VERSION 5.7 ;
  NOWIREEXTENSIONATPIN ON ;
  DIVIDERCHAR "/" ;
  BUSBITCHARS "[]" ;
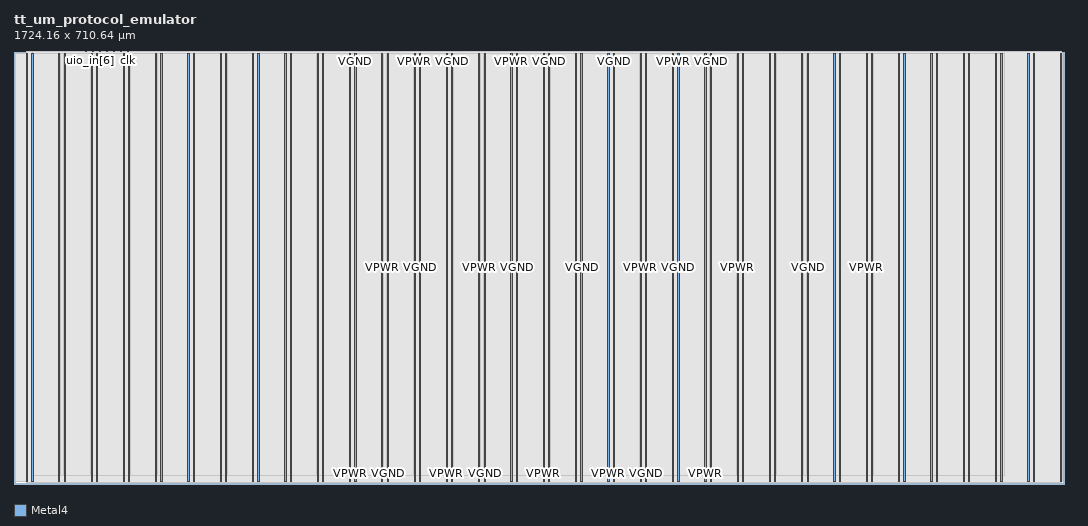
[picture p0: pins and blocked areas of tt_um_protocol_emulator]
MACRO tt_um_protocol_emulator
  CLASS BLOCK ;
  FOREIGN tt_um_protocol_emulator ;
  ORIGIN 0.000 0.000 ;
  SIZE 1724.160 BY 710.640 ;
  PIN VGND
    DIRECTION INOUT ;
    USE GROUND ;
    PORT
      LAYER Metal4 ;
        RECT 1143.055 3.560 1145.155 707.080 ;
    END
  END VGND
  PIN VGND
    DIRECTION INOUT ;
    USE GROUND ;
    PORT
      LAYER Metal4 ;
        RECT 1090.015 3.560 1092.115 707.080 ;
    END
  END VGND
  PIN VGND
    DIRECTION INOUT ;
    USE GROUND ;
    PORT
      LAYER Metal4 ;
        RECT 1036.975 3.560 1039.075 707.080 ;
    END
  END VGND
  PIN VGND
    DIRECTION INOUT ;
    USE GROUND ;
    PORT
      LAYER Metal4 ;
        RECT 983.935 3.560 986.035 707.080 ;
    END
  END VGND
  PIN VGND
    DIRECTION INOUT ;
    USE GROUND ;
    PORT
      LAYER Metal4 ;
        RECT 930.895 3.560 932.995 707.080 ;
    END
  END VGND
  PIN VGND
    DIRECTION INOUT ;
    USE GROUND ;
    PORT
      LAYER Metal4 ;
        RECT 877.855 3.560 879.955 707.080 ;
    END
  END VGND
  PIN VGND
    DIRECTION INOUT ;
    USE GROUND ;
    PORT
      LAYER Metal4 ;
        RECT 824.815 3.560 826.915 707.080 ;
    END
  END VGND
  PIN VGND
    DIRECTION INOUT ;
    USE GROUND ;
    PORT
      LAYER Metal4 ;
        RECT 771.775 3.560 773.875 707.080 ;
    END
  END VGND
  PIN VGND
    DIRECTION INOUT ;
    USE GROUND ;
    PORT
      LAYER Metal4 ;
        RECT 718.735 3.560 720.835 707.080 ;
    END
  END VGND
  PIN VGND
    DIRECTION INOUT ;
    USE GROUND ;
    PORT
      LAYER Metal4 ;
        RECT 665.695 3.560 667.795 707.080 ;
    END
  END VGND
  PIN VGND
    DIRECTION INOUT ;
    USE GROUND ;
    PORT
      LAYER Metal4 ;
        RECT 612.655 3.560 614.755 707.080 ;
    END
  END VGND
  PIN VGND
    DIRECTION INOUT ;
    USE GROUND ;
    PORT
      LAYER Metal4 ;
        RECT 559.615 3.560 561.715 707.080 ;
    END
  END VGND
  PIN VGND
    DIRECTION INOUT ;
    USE GROUND ;
    PORT
      LAYER Metal4 ;
        RECT 29.215 3.560 31.315 707.080 ;
    END
    PORT
      LAYER Metal4 ;
        RECT 82.255 3.560 84.355 707.080 ;
    END
    PORT
      LAYER Metal4 ;
        RECT 135.295 3.560 137.395 707.080 ;
    END
    PORT
      LAYER Metal4 ;
        RECT 188.335 3.560 190.435 707.080 ;
    END
    PORT
      LAYER Metal4 ;
        RECT 241.375 3.560 243.475 707.080 ;
    END
    PORT
      LAYER Metal4 ;
        RECT 294.415 3.560 296.515 707.080 ;
    END
    PORT
      LAYER Metal4 ;
        RECT 347.455 3.560 349.555 707.080 ;
    END
    PORT
      LAYER Metal4 ;
        RECT 400.495 3.560 402.595 707.080 ;
    END
    PORT
      LAYER Metal4 ;
        RECT 453.535 3.560 455.635 707.080 ;
    END
    PORT
      LAYER Metal4 ;
        RECT 506.575 3.560 508.675 707.080 ;
    END
    PORT
      LAYER Metal4 ;
        RECT 1196.095 3.560 1198.195 707.080 ;
    END
    PORT
      LAYER Metal4 ;
        RECT 1249.135 3.560 1251.235 707.080 ;
    END
    PORT
      LAYER Metal4 ;
        RECT 1302.175 3.560 1304.275 707.080 ;
    END
    PORT
      LAYER Metal4 ;
        RECT 1355.215 3.560 1357.315 707.080 ;
    END
    PORT
      LAYER Metal4 ;
        RECT 1408.255 3.560 1410.355 707.080 ;
    END
    PORT
      LAYER Metal4 ;
        RECT 1461.295 3.560 1463.395 707.080 ;
    END
    PORT
      LAYER Metal4 ;
        RECT 1514.335 3.560 1516.435 707.080 ;
    END
    PORT
      LAYER Metal4 ;
        RECT 1567.375 3.560 1569.475 707.080 ;
    END
    PORT
      LAYER Metal4 ;
        RECT 1620.415 3.560 1622.515 707.080 ;
    END
    PORT
      LAYER Metal4 ;
        RECT 1673.455 3.560 1675.555 707.080 ;
    END
  END VGND
  PIN VPWR
    DIRECTION INOUT ;
    USE POWER ;
    PORT
      LAYER Metal4 ;
        RECT 1187.255 3.560 1189.355 707.080 ;
    END
  END VPWR
  PIN VPWR
    DIRECTION INOUT ;
    USE POWER ;
    PORT
      LAYER Metal4 ;
        RECT 1134.215 3.560 1136.315 707.080 ;
    END
  END VPWR
  PIN VPWR
    DIRECTION INOUT ;
    USE POWER ;
    PORT
      LAYER Metal4 ;
        RECT 1081.175 3.560 1083.275 707.080 ;
    END
  END VPWR
  PIN VPWR
    DIRECTION INOUT ;
    USE POWER ;
    PORT
      LAYER Metal4 ;
        RECT 1028.135 3.560 1030.235 707.080 ;
    END
  END VPWR
  PIN VPWR
    DIRECTION INOUT ;
    USE POWER ;
    PORT
      LAYER Metal4 ;
        RECT 975.095 3.560 977.195 707.080 ;
    END
  END VPWR
  PIN VPWR
    DIRECTION INOUT ;
    USE POWER ;
    PORT
      LAYER Metal4 ;
        RECT 922.055 3.560 924.155 707.080 ;
    END
  END VPWR
  PIN VPWR
    DIRECTION INOUT ;
    USE POWER ;
    PORT
      LAYER Metal4 ;
        RECT 869.015 3.560 871.115 707.080 ;
    END
  END VPWR
  PIN VPWR
    DIRECTION INOUT ;
    USE POWER ;
    PORT
      LAYER Metal4 ;
        RECT 815.975 3.560 818.075 707.080 ;
    END
  END VPWR
  PIN VPWR
    DIRECTION INOUT ;
    USE POWER ;
    PORT
      LAYER Metal4 ;
        RECT 762.935 3.560 765.035 707.080 ;
    END
  END VPWR
  PIN VPWR
    DIRECTION INOUT ;
    USE POWER ;
    PORT
      LAYER Metal4 ;
        RECT 709.895 3.560 711.995 707.080 ;
    END
  END VPWR
  PIN VPWR
    DIRECTION INOUT ;
    USE POWER ;
    PORT
      LAYER Metal4 ;
        RECT 656.855 3.560 658.955 707.080 ;
    END
  END VPWR
  PIN VPWR
    DIRECTION INOUT ;
    USE POWER ;
    PORT
      LAYER Metal4 ;
        RECT 603.815 3.560 605.915 707.080 ;
    END
  END VPWR
  PIN VPWR
    DIRECTION INOUT ;
    USE POWER ;
    PORT
      LAYER Metal4 ;
        RECT 550.775 3.560 552.875 707.080 ;
    END
  END VPWR
  PIN VPWR
    DIRECTION INOUT ;
    USE POWER ;
    PORT
      LAYER Metal4 ;
        RECT 20.375 3.560 22.475 707.080 ;
    END
    PORT
      LAYER Metal4 ;
        RECT 73.415 3.560 75.515 707.080 ;
    END
    PORT
      LAYER Metal4 ;
        RECT 126.455 3.560 128.555 707.080 ;
    END
    PORT
      LAYER Metal4 ;
        RECT 179.495 3.560 181.595 707.080 ;
    END
    PORT
      LAYER Metal4 ;
        RECT 232.535 3.560 234.635 707.080 ;
    END
    PORT
      LAYER Metal4 ;
        RECT 285.575 3.560 287.675 707.080 ;
    END
    PORT
      LAYER Metal4 ;
        RECT 338.615 3.560 340.715 707.080 ;
    END
    PORT
      LAYER Metal4 ;
        RECT 391.655 3.560 393.755 707.080 ;
    END
    PORT
      LAYER Metal4 ;
        RECT 444.695 3.560 446.795 707.080 ;
    END
    PORT
      LAYER Metal4 ;
        RECT 497.735 3.560 499.835 707.080 ;
    END
    PORT
      LAYER Metal4 ;
        RECT 1240.295 3.560 1242.395 707.080 ;
    END
    PORT
      LAYER Metal4 ;
        RECT 1293.335 3.560 1295.435 707.080 ;
    END
    PORT
      LAYER Metal4 ;
        RECT 1346.375 3.560 1348.475 707.080 ;
    END
    PORT
      LAYER Metal4 ;
        RECT 1399.415 3.560 1401.515 707.080 ;
    END
    PORT
      LAYER Metal4 ;
        RECT 1452.455 3.560 1454.555 707.080 ;
    END
    PORT
      LAYER Metal4 ;
        RECT 1505.495 3.560 1507.595 707.080 ;
    END
    PORT
      LAYER Metal4 ;
        RECT 1558.535 3.560 1560.635 707.080 ;
    END
    PORT
      LAYER Metal4 ;
        RECT 1611.575 3.560 1613.675 707.080 ;
    END
    PORT
      LAYER Metal4 ;
        RECT 1664.615 3.560 1666.715 707.080 ;
    END
    PORT
      LAYER Metal4 ;
        RECT 1717.655 3.560 1719.755 707.080 ;
    END
  END VPWR
  PIN clk
    DIRECTION INPUT ;
    USE SIGNAL ;
    ANTENNAGATEAREA 1.450800 ;
    PORT
      LAYER Metal4 ;
        RECT 187.050 709.640 187.350 710.640 ;
    END
  END clk
  PIN ena
    DIRECTION INPUT ;
    USE SIGNAL ;
    PORT
      LAYER Metal4 ;
        RECT 190.890 709.640 191.190 710.640 ;
    END
  END ena
  PIN rst_n
    DIRECTION INPUT ;
    USE SIGNAL ;
    ANTENNAGATEAREA 0.180700 ;
    PORT
      LAYER Metal4 ;
        RECT 183.210 709.640 183.510 710.640 ;
    END
  END rst_n
  PIN ui_in[0]
    DIRECTION INPUT ;
    USE SIGNAL ;
    ANTENNAGATEAREA 0.180700 ;
    PORT
      LAYER Metal4 ;
        RECT 179.370 709.640 179.670 710.640 ;
    END
  END ui_in[0]
  PIN ui_in[1]
    DIRECTION INPUT ;
    USE SIGNAL ;
    ANTENNAGATEAREA 0.180700 ;
    PORT
      LAYER Metal4 ;
        RECT 175.530 709.640 175.830 710.640 ;
    END
  END ui_in[1]
  PIN ui_in[2]
    DIRECTION INPUT ;
    USE SIGNAL ;
    ANTENNAGATEAREA 0.180700 ;
    PORT
      LAYER Metal4 ;
        RECT 171.690 709.640 171.990 710.640 ;
    END
  END ui_in[2]
  PIN ui_in[3]
    DIRECTION INPUT ;
    USE SIGNAL ;
    ANTENNAGATEAREA 0.180700 ;
    PORT
      LAYER Metal4 ;
        RECT 167.850 709.640 168.150 710.640 ;
    END
  END ui_in[3]
  PIN ui_in[4]
    DIRECTION INPUT ;
    USE SIGNAL ;
    ANTENNAGATEAREA 0.180700 ;
    PORT
      LAYER Metal4 ;
        RECT 164.010 709.640 164.310 710.640 ;
    END
  END ui_in[4]
  PIN ui_in[5]
    DIRECTION INPUT ;
    USE SIGNAL ;
    ANTENNAGATEAREA 0.180700 ;
    PORT
      LAYER Metal4 ;
        RECT 160.170 709.640 160.470 710.640 ;
    END
  END ui_in[5]
  PIN ui_in[6]
    DIRECTION INPUT ;
    USE SIGNAL ;
    ANTENNAGATEAREA 0.180700 ;
    PORT
      LAYER Metal4 ;
        RECT 156.330 709.640 156.630 710.640 ;
    END
  END ui_in[6]
  PIN ui_in[7]
    DIRECTION INPUT ;
    USE SIGNAL ;
    ANTENNAGATEAREA 0.180700 ;
    PORT
      LAYER Metal4 ;
        RECT 152.490 709.640 152.790 710.640 ;
    END
  END ui_in[7]
  PIN uio_in[0]
    DIRECTION INPUT ;
    USE SIGNAL ;
    ANTENNAGATEAREA 0.180700 ;
    PORT
      LAYER Metal4 ;
        RECT 148.650 709.640 148.950 710.640 ;
    END
  END uio_in[0]
  PIN uio_in[1]
    DIRECTION INPUT ;
    USE SIGNAL ;
    ANTENNAGATEAREA 0.180700 ;
    PORT
      LAYER Metal4 ;
        RECT 144.810 709.640 145.110 710.640 ;
    END
  END uio_in[1]
  PIN uio_in[2]
    DIRECTION INPUT ;
    USE SIGNAL ;
    ANTENNAGATEAREA 0.180700 ;
    PORT
      LAYER Metal4 ;
        RECT 140.970 709.640 141.270 710.640 ;
    END
  END uio_in[2]
  PIN uio_in[3]
    DIRECTION INPUT ;
    USE SIGNAL ;
    ANTENNAGATEAREA 0.180700 ;
    PORT
      LAYER Metal4 ;
        RECT 137.130 709.640 137.430 710.640 ;
    END
  END uio_in[3]
  PIN uio_in[4]
    DIRECTION INPUT ;
    USE SIGNAL ;
    ANTENNAGATEAREA 0.180700 ;
    PORT
      LAYER Metal4 ;
        RECT 133.290 709.640 133.590 710.640 ;
    END
  END uio_in[4]
  PIN uio_in[5]
    DIRECTION INPUT ;
    USE SIGNAL ;
    ANTENNAGATEAREA 0.180700 ;
    PORT
      LAYER Metal4 ;
        RECT 129.450 709.640 129.750 710.640 ;
    END
  END uio_in[5]
  PIN uio_in[6]
    DIRECTION INPUT ;
    USE SIGNAL ;
    ANTENNAGATEAREA 0.180700 ;
    PORT
      LAYER Metal4 ;
        RECT 125.610 709.640 125.910 710.640 ;
    END
  END uio_in[6]
  PIN uio_in[7]
    DIRECTION INPUT ;
    USE SIGNAL ;
    ANTENNAGATEAREA 0.180700 ;
    PORT
      LAYER Metal4 ;
        RECT 121.770 709.640 122.070 710.640 ;
    END
  END uio_in[7]
  PIN uio_oe[0]
    DIRECTION OUTPUT ;
    USE SIGNAL ;
    ANTENNADIFFAREA 0.708600 ;
    PORT
      LAYER Metal4 ;
        RECT 56.490 709.640 56.790 710.640 ;
    END
  END uio_oe[0]
  PIN uio_oe[1]
    DIRECTION OUTPUT ;
    USE SIGNAL ;
    ANTENNADIFFAREA 0.708600 ;
    PORT
      LAYER Metal4 ;
        RECT 52.650 709.640 52.950 710.640 ;
    END
  END uio_oe[1]
  PIN uio_oe[2]
    DIRECTION OUTPUT ;
    USE SIGNAL ;
    ANTENNADIFFAREA 0.708600 ;
    PORT
      LAYER Metal4 ;
        RECT 48.810 709.640 49.110 710.640 ;
    END
  END uio_oe[2]
  PIN uio_oe[3]
    DIRECTION OUTPUT ;
    USE SIGNAL ;
    ANTENNADIFFAREA 0.708600 ;
    PORT
      LAYER Metal4 ;
        RECT 44.970 709.640 45.270 710.640 ;
    END
  END uio_oe[3]
  PIN uio_oe[4]
    DIRECTION OUTPUT ;
    USE SIGNAL ;
    ANTENNADIFFAREA 0.708600 ;
    PORT
      LAYER Metal4 ;
        RECT 41.130 709.640 41.430 710.640 ;
    END
  END uio_oe[4]
  PIN uio_oe[5]
    DIRECTION OUTPUT ;
    USE SIGNAL ;
    ANTENNADIFFAREA 0.708600 ;
    PORT
      LAYER Metal4 ;
        RECT 37.290 709.640 37.590 710.640 ;
    END
  END uio_oe[5]
  PIN uio_oe[6]
    DIRECTION OUTPUT ;
    USE SIGNAL ;
    ANTENNADIFFAREA 0.708600 ;
    PORT
      LAYER Metal4 ;
        RECT 33.450 709.640 33.750 710.640 ;
    END
  END uio_oe[6]
  PIN uio_oe[7]
    DIRECTION OUTPUT ;
    USE SIGNAL ;
    ANTENNADIFFAREA 0.708600 ;
    PORT
      LAYER Metal4 ;
        RECT 29.610 709.640 29.910 710.640 ;
    END
  END uio_oe[7]
  PIN uio_out[0]
    DIRECTION OUTPUT ;
    USE SIGNAL ;
    ANTENNADIFFAREA 0.708600 ;
    PORT
      LAYER Metal4 ;
        RECT 87.210 709.640 87.510 710.640 ;
    END
  END uio_out[0]
  PIN uio_out[1]
    DIRECTION OUTPUT ;
    USE SIGNAL ;
    ANTENNADIFFAREA 0.708600 ;
    PORT
      LAYER Metal4 ;
        RECT 83.370 709.640 83.670 710.640 ;
    END
  END uio_out[1]
  PIN uio_out[2]
    DIRECTION OUTPUT ;
    USE SIGNAL ;
    ANTENNADIFFAREA 0.708600 ;
    PORT
      LAYER Metal4 ;
        RECT 79.530 709.640 79.830 710.640 ;
    END
  END uio_out[2]
  PIN uio_out[3]
    DIRECTION OUTPUT ;
    USE SIGNAL ;
    ANTENNADIFFAREA 0.708600 ;
    PORT
      LAYER Metal4 ;
        RECT 75.690 709.640 75.990 710.640 ;
    END
  END uio_out[3]
  PIN uio_out[4]
    DIRECTION OUTPUT ;
    USE SIGNAL ;
    ANTENNADIFFAREA 0.708600 ;
    PORT
      LAYER Metal4 ;
        RECT 71.850 709.640 72.150 710.640 ;
    END
  END uio_out[4]
  PIN uio_out[5]
    DIRECTION OUTPUT ;
    USE SIGNAL ;
    ANTENNADIFFAREA 0.708600 ;
    PORT
      LAYER Metal4 ;
        RECT 68.010 709.640 68.310 710.640 ;
    END
  END uio_out[5]
  PIN uio_out[6]
    DIRECTION OUTPUT ;
    USE SIGNAL ;
    ANTENNADIFFAREA 0.708600 ;
    PORT
      LAYER Metal4 ;
        RECT 64.170 709.640 64.470 710.640 ;
    END
  END uio_out[6]
  PIN uio_out[7]
    DIRECTION OUTPUT ;
    USE SIGNAL ;
    ANTENNADIFFAREA 0.708600 ;
    PORT
      LAYER Metal4 ;
        RECT 60.330 709.640 60.630 710.640 ;
    END
  END uio_out[7]
  PIN uo_out[0]
    DIRECTION OUTPUT ;
    USE SIGNAL ;
    ANTENNADIFFAREA 0.708600 ;
    PORT
      LAYER Metal4 ;
        RECT 117.930 709.640 118.230 710.640 ;
    END
  END uo_out[0]
  PIN uo_out[1]
    DIRECTION OUTPUT ;
    USE SIGNAL ;
    ANTENNADIFFAREA 0.708600 ;
    PORT
      LAYER Metal4 ;
        RECT 114.090 709.640 114.390 710.640 ;
    END
  END uo_out[1]
  PIN uo_out[2]
    DIRECTION OUTPUT ;
    USE SIGNAL ;
    ANTENNADIFFAREA 0.708600 ;
    PORT
      LAYER Metal4 ;
        RECT 110.250 709.640 110.550 710.640 ;
    END
  END uo_out[2]
  PIN uo_out[3]
    DIRECTION OUTPUT ;
    USE SIGNAL ;
    ANTENNADIFFAREA 0.708600 ;
    PORT
      LAYER Metal4 ;
        RECT 106.410 709.640 106.710 710.640 ;
    END
  END uo_out[3]
  PIN uo_out[4]
    DIRECTION OUTPUT ;
    USE SIGNAL ;
    ANTENNADIFFAREA 0.708600 ;
    PORT
      LAYER Metal4 ;
        RECT 102.570 709.640 102.870 710.640 ;
    END
  END uo_out[4]
  PIN uo_out[5]
    DIRECTION OUTPUT ;
    USE SIGNAL ;
    ANTENNADIFFAREA 0.708600 ;
    PORT
      LAYER Metal4 ;
        RECT 98.730 709.640 99.030 710.640 ;
    END
  END uo_out[5]
  PIN uo_out[6]
    DIRECTION OUTPUT ;
    USE SIGNAL ;
    ANTENNADIFFAREA 0.708600 ;
    PORT
      LAYER Metal4 ;
        RECT 94.890 709.640 95.190 710.640 ;
    END
  END uo_out[6]
  PIN uo_out[7]
    DIRECTION OUTPUT ;
    USE SIGNAL ;
    ANTENNADIFFAREA 0.708600 ;
    PORT
      LAYER Metal4 ;
        RECT 91.050 709.640 91.350 710.640 ;
    END
  END uo_out[7]
  OBS
      LAYER GatPoly ;
        RECT 2.880 3.630 1721.280 707.010 ;
      LAYER Metal1 ;
        RECT 2.880 3.560 1721.280 707.080 ;
      LAYER Metal2 ;
        RECT 20.505 2.375 1719.625 709.945 ;
      LAYER Metal3 ;
        RECT 20.460 2.420 1719.670 709.905 ;
      LAYER Metal4 ;
        RECT 30.120 709.430 33.240 709.945 ;
        RECT 33.960 709.430 37.080 709.945 ;
        RECT 37.800 709.430 40.920 709.945 ;
        RECT 41.640 709.430 44.760 709.945 ;
        RECT 45.480 709.430 48.600 709.945 ;
        RECT 49.320 709.430 52.440 709.945 ;
        RECT 53.160 709.430 56.280 709.945 ;
        RECT 57.000 709.430 60.120 709.945 ;
        RECT 60.840 709.430 63.960 709.945 ;
        RECT 64.680 709.430 67.800 709.945 ;
        RECT 68.520 709.430 71.640 709.945 ;
        RECT 72.360 709.430 75.480 709.945 ;
        RECT 76.200 709.430 79.320 709.945 ;
        RECT 80.040 709.430 83.160 709.945 ;
        RECT 83.880 709.430 87.000 709.945 ;
        RECT 87.720 709.430 90.840 709.945 ;
        RECT 91.560 709.430 94.680 709.945 ;
        RECT 95.400 709.430 98.520 709.945 ;
        RECT 99.240 709.430 102.360 709.945 ;
        RECT 103.080 709.430 106.200 709.945 ;
        RECT 106.920 709.430 110.040 709.945 ;
        RECT 110.760 709.430 113.880 709.945 ;
        RECT 114.600 709.430 117.720 709.945 ;
        RECT 118.440 709.430 121.560 709.945 ;
        RECT 122.280 709.430 125.400 709.945 ;
        RECT 126.120 709.430 129.240 709.945 ;
        RECT 129.960 709.430 133.080 709.945 ;
        RECT 133.800 709.430 136.920 709.945 ;
        RECT 137.640 709.430 140.760 709.945 ;
        RECT 141.480 709.430 144.600 709.945 ;
        RECT 145.320 709.430 148.440 709.945 ;
        RECT 149.160 709.430 152.280 709.945 ;
        RECT 153.000 709.430 156.120 709.945 ;
        RECT 156.840 709.430 159.960 709.945 ;
        RECT 160.680 709.430 163.800 709.945 ;
        RECT 164.520 709.430 167.640 709.945 ;
        RECT 168.360 709.430 171.480 709.945 ;
        RECT 172.200 709.430 175.320 709.945 ;
        RECT 176.040 709.430 179.160 709.945 ;
        RECT 179.880 709.430 183.000 709.945 ;
        RECT 183.720 709.430 186.840 709.945 ;
        RECT 187.560 709.430 190.680 709.945 ;
        RECT 191.400 709.430 1626.820 709.945 ;
        RECT 29.660 707.290 1626.820 709.430 ;
        RECT 31.525 13.780 73.205 707.290 ;
        RECT 75.725 13.780 82.045 707.290 ;
        RECT 84.565 13.780 126.245 707.290 ;
        RECT 128.765 13.780 135.085 707.290 ;
        RECT 137.605 13.780 179.285 707.290 ;
        RECT 181.805 13.780 188.125 707.290 ;
        RECT 190.645 13.780 232.325 707.290 ;
        RECT 234.845 13.780 241.165 707.290 ;
        RECT 243.685 13.780 285.365 707.290 ;
        RECT 287.885 13.780 294.205 707.290 ;
        RECT 296.725 13.780 338.405 707.290 ;
        RECT 340.925 13.780 347.245 707.290 ;
        RECT 349.765 13.780 391.445 707.290 ;
        RECT 393.965 13.780 400.285 707.290 ;
        RECT 402.805 13.780 444.485 707.290 ;
        RECT 447.005 13.780 453.325 707.290 ;
        RECT 455.845 13.780 497.525 707.290 ;
        RECT 500.045 13.780 506.365 707.290 ;
        RECT 508.885 13.780 550.565 707.290 ;
        RECT 553.085 13.780 559.405 707.290 ;
        RECT 561.925 13.780 603.605 707.290 ;
        RECT 606.125 13.780 612.445 707.290 ;
        RECT 614.965 13.780 656.645 707.290 ;
        RECT 659.165 13.780 665.485 707.290 ;
        RECT 668.005 13.780 709.685 707.290 ;
        RECT 712.205 13.780 718.525 707.290 ;
        RECT 721.045 13.780 762.725 707.290 ;
        RECT 765.245 13.780 771.565 707.290 ;
        RECT 774.085 13.780 815.765 707.290 ;
        RECT 818.285 13.780 824.605 707.290 ;
        RECT 827.125 13.780 868.805 707.290 ;
        RECT 871.325 13.780 877.645 707.290 ;
        RECT 880.165 13.780 921.845 707.290 ;
        RECT 924.365 13.780 930.685 707.290 ;
        RECT 933.205 13.780 974.885 707.290 ;
        RECT 977.405 13.780 983.725 707.290 ;
        RECT 986.245 13.780 1027.925 707.290 ;
        RECT 1030.445 13.780 1036.765 707.290 ;
        RECT 1039.285 13.780 1080.965 707.290 ;
        RECT 1083.485 13.780 1089.805 707.290 ;
        RECT 1092.325 13.780 1134.005 707.290 ;
        RECT 1136.525 13.780 1142.845 707.290 ;
        RECT 1145.365 13.780 1187.045 707.290 ;
        RECT 1189.565 13.780 1195.885 707.290 ;
        RECT 1198.405 13.780 1240.085 707.290 ;
        RECT 1242.605 13.780 1248.925 707.290 ;
        RECT 1251.445 13.780 1293.125 707.290 ;
        RECT 1295.645 13.780 1301.965 707.290 ;
        RECT 1304.485 13.780 1346.165 707.290 ;
        RECT 1348.685 13.780 1355.005 707.290 ;
        RECT 1357.525 13.780 1399.205 707.290 ;
        RECT 1401.725 13.780 1408.045 707.290 ;
        RECT 1410.565 13.780 1452.245 707.290 ;
        RECT 1454.765 13.780 1461.085 707.290 ;
        RECT 1463.605 13.780 1505.285 707.290 ;
        RECT 1507.805 13.780 1514.125 707.290 ;
        RECT 1516.645 13.780 1558.325 707.290 ;
        RECT 1560.845 13.780 1567.165 707.290 ;
        RECT 1569.685 13.780 1611.365 707.290 ;
        RECT 1613.885 13.780 1620.205 707.290 ;
        RECT 1622.725 13.780 1626.820 707.290 ;
  END
END tt_um_protocol_emulator
END LIBRARY

